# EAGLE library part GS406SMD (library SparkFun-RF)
50 Channel GS406 Helical GPS Receiver - SMD Connector. The Mating SMD SPECIAL is called SPECIAL for a reason. This package was only made in order to make a dummy gs407 PCB with mating connector (used for testing). sku: GPS-09079

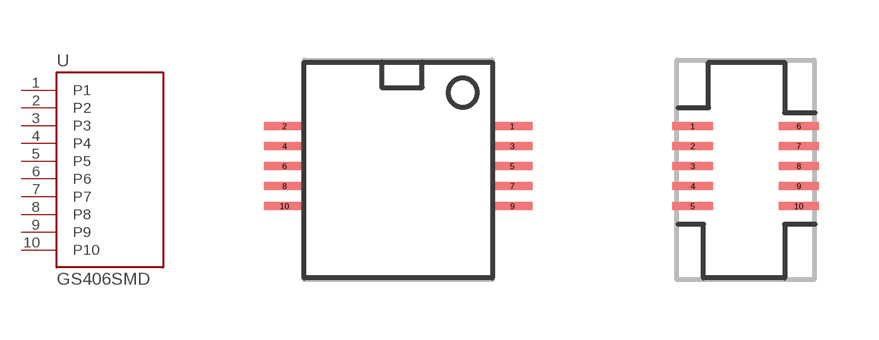
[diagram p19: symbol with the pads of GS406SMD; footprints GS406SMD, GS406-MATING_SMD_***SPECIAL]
Designator prefix U

## GS406SMDSOCKET  [GS406SMD]
1  P1
2  P2
3  P3
4  P4
5  P5
6  P6
7  P7
8  P8
9  P9
10  P10

## GS406SMDMATING_SMD_***SPECIAL  [GS406-MATING_SMD_***SPECIAL]
Pads as for GS406SMD

## Footprint GS406SMD (pad centres in mm)
50 Channel GS406 Helical GPS Receiver - SMD Connector sku: GPS-09079
smd 1 x 0.2: 1 2.76,1.06; 2 -2.94,1.06; 3 2.76,0.56; 4 -2.94,0.56; 5 2.76,0.06; 6 -2.94,0.06; 7 2.76,-0.44; 8 -2.94,-0.44; 9 2.76,-0.94; 10 -2.94,-0.94

## Footprint GS406-MATING_SMD_***SPECIAL (pad centres in mm)
smd 1 x 0.2: 1 -1.289,1.06; 2 -1.289,0.56; 3 -1.289,0.06; 4 -1.289,-0.44; 5 -1.289,-0.94; 6 1.363,1.06; 7 1.363,0.56; 8 1.363,0.06; 9 1.363,-0.44; 10 1.363,-0.94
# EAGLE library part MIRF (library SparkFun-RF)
nRF2401A 2.4GHz transceiver module, WRL-00153

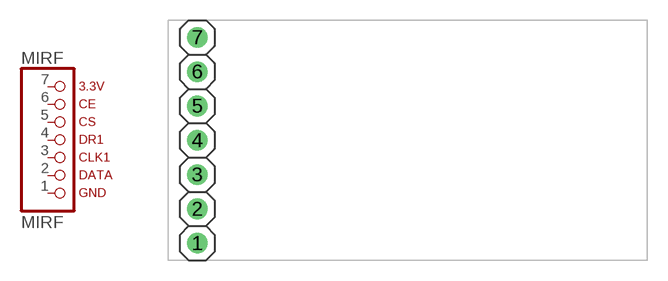
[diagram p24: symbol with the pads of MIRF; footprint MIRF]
Designator prefix MIRF

## MIRF  [MIRF]
1  7  pas
2  6  pas
3  5  pas
4  4  pas
5  3  pas
6  2  pas
7  1  pas

## Footprint MIRF (pad centres in mm)
PIN HEADER
drill 1.016: 1 0,-7.62; 2 0,-5.08; 3 0,-2.54; 4 0,0; 5 0,2.54; 6 0,5.08; 7 0,7.62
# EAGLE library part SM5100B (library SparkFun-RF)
Quad-band GSM modem

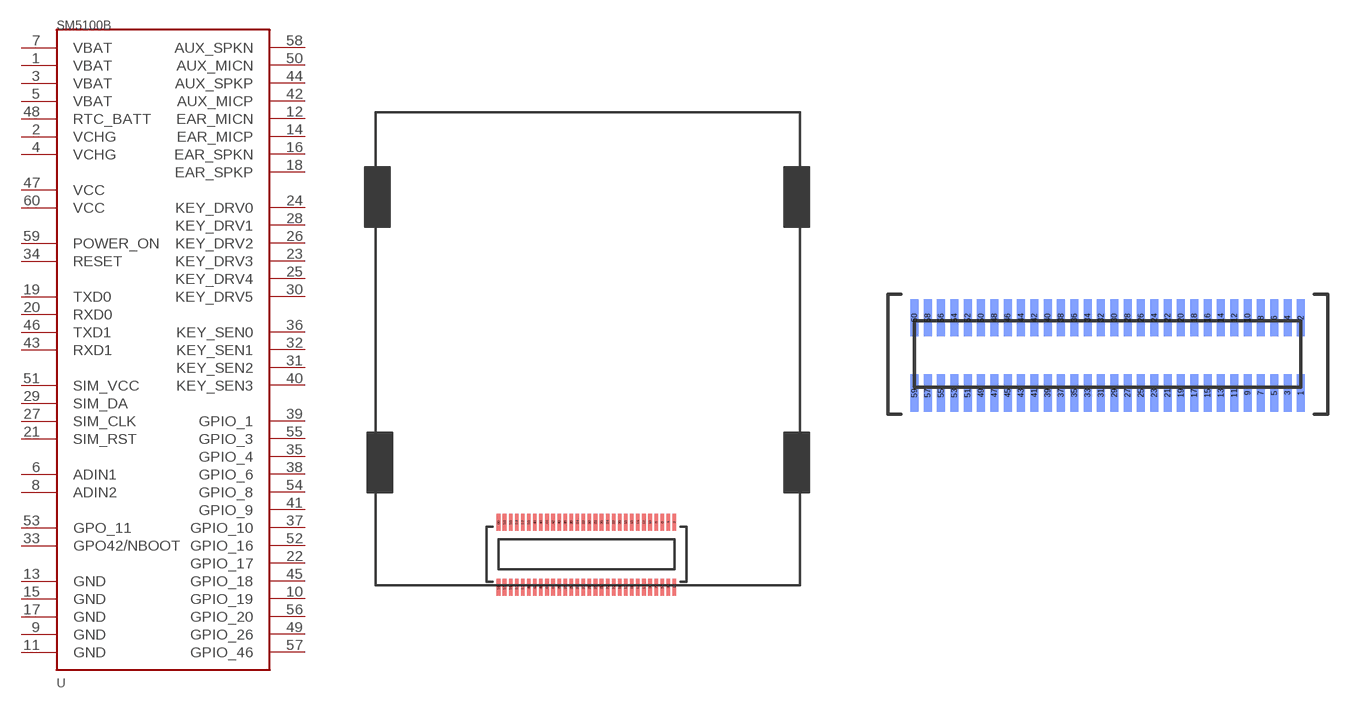
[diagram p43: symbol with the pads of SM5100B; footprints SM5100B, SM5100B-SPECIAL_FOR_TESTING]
Designator prefix -

## SM5100B (PROD_ID: CONN-09315)  [SM5100B]
1  VBAT
2  VCHG
3  VBAT
4  VCHG
5  VBAT
6  ADIN1
7  VBAT
8  ADIN2
9  GND
10  GPIO_19
11  GND
12  EAR_MICN
13  GND
14  EAR_MICP
15  GND
16  EAR_SPKN
17  GND
18  EAR_SPKP
19  TXD0
20  RXD0
21  SIM_RST
22  GPIO_17
23  KEY_DRV3
24  KEY_DRV0
25  KEY_DRV4
26  KEY_DRV2
27  SIM_CLK
28  KEY_DRV1
29  SIM_DA
30  KEY_DRV5
31  KEY_SEN2
32  KEY_SEN1
33  GPO42/NBOOT
34  RESET
35  GPIO_4
36  KEY_SEN0
37  GPIO_10
38  GPIO_6
39  GPIO_1
40  KEY_SEN3
41  GPIO_9
42  AUX_MICP
43  RXD1
44  AUX_SPKP
45  GPIO_18
46  TXD1
47  VCC
48  RTC_BATT
49  GPIO_26
50  AUX_MICN
51  SIM_VCC
52  GPIO_16
53  GPO_11
54  GPIO_8
55  GPIO_3
56  GPIO_20
57  GPIO_46
58  AUX_SPKN
59  POWER_ON
60  VCC

## SM5100BSPECIAL_FOR_TESTING!!  [SM5100B-SPECIAL_FOR_TESTING]
Pads as for SM5100B

## Footprint SM5100B (pad centres in mm)
smd 0.3 x 1.4: 1 7.25,-2.68; 2 7.25,2.68; 3 6.75,-2.68; 4 6.75,2.68; 5 6.25,-2.68; 6 6.25,2.68; 7 5.75,-2.68; 8 5.75,2.68; 9 5.25,-2.68; 10 5.25,2.68; 11 4.75,-2.68; 12 4.75,2.68; 13 4.25,-2.68; 14 4.25,2.68; 15 3.75,-2.68; 16 3.75,2.68; 17 3.25,-2.68; 18 3.25,2.68; 19 2.75,-2.68; 20 2.75,2.68; 21 2.25,-2.68; 22 2.25,2.68; 23 1.75,-2.68; 24 1.75,2.68; 25 1.25,-2.68; 26 1.25,2.68; 27 0.75,-2.68; 28 0.75,2.68; 29 0.25,-2.68; 30 0.25,2.68; 31 -0.25,-2.68; 32 -0.25,2.68; 33 -0.75,-2.68; 34 -0.75,2.68; 35 -1.25,-2.68; 36 -1.25,2.68; 37 -1.75,-2.68; 38 -1.75,2.68; 39 -2.25,-2.68; 40 -2.25,2.68; 41 -2.75,-2.68; 42 -2.75,2.68; 43 -3.25,-2.68; 44 -3.25,2.68; 45 -3.75,-2.68; 46 -3.75,2.68; 47 -4.25,-2.68; 48 -4.25,2.68; 49 -4.75,-2.68; 50 -4.75,2.68; 51 -5.25,-2.68; 52 -5.25,2.68; 53 -5.75,-2.68; 54 -5.75,2.68; 55 -6.25,-2.68; 56 -6.25,2.68; 57 -6.75,-2.68; 58 -6.75,2.68; 59 -7.25,-2.68; 60 -7.25,2.68

## Footprint SM5100B-SPECIAL_FOR_TESTING (pad centres in mm)
smd 0.3 x 1.4 bottom: 1 7.25,-1.41; 2 7.25,1.41; 3 6.75,-1.41; 4 6.75,1.41; 5 6.25,-1.41; 6 6.25,1.41; 7 5.75,-1.41; 8 5.75,1.41; 9 5.25,-1.41; 10 5.25,1.41; 11 4.75,-1.41; 12 4.75,1.41; 13 4.25,-1.41; 14 4.25,1.41; 15 3.75,-1.41; 16 3.75,1.41; 17 3.25,-1.41; 18 3.25,1.41; 19 2.75,-1.41; 20 2.75,1.41; 21 2.25,-1.41; 22 2.25,1.41; 23 1.75,-1.41; 24 1.75,1.41; 25 1.25,-1.41; 26 1.25,1.41; 27 0.75,-1.41; 28 0.75,1.41; 29 0.25,-1.41; 30 0.25,1.41; 31 -0.25,-1.41; 32 -0.25,1.41; 33 -0.75,-1.41; 34 -0.75,1.41; 35 -1.25,-1.41; 36 -1.25,1.41; 37 -1.75,-1.41; 38 -1.75,1.41; 39 -2.25,-1.41; 40 -2.25,1.41; 41 -2.75,-1.41; 42 -2.75,1.41; 43 -3.25,-1.41; 44 -3.25,1.41; 45 -3.75,-1.41; 46 -3.75,1.41; 47 -4.25,-1.41; 48 -4.25,1.41; 49 -4.75,-1.41; 50 -4.75,1.41; 51 -5.25,-1.41; 52 -5.25,1.41; 53 -5.75,-1.41; 54 -5.75,1.41; 55 -6.25,-1.41; 56 -6.25,1.41; 57 -6.75,-1.41; 58 -6.75,1.41; 59 -7.25,-1.41; 60 -7.25,1.41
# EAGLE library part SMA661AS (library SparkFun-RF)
GPS low noise amplifier, 18dB gain, low external parts count

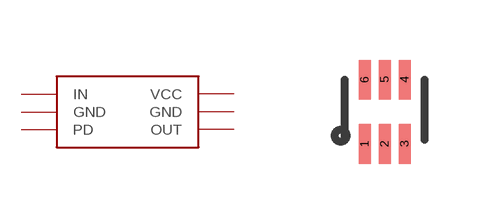
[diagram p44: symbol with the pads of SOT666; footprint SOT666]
Designator prefix -

## SMA661AS  [SOT666]
1  IN
2  GND
3  PD
4  OUT
5  GND
6  VCC

## Footprint SOT666 (pad centres in mm)
smd 0.3 x 0.99: 1 0,0; 2 0.5,0; 3 1,0; 4 1,1.61; 5 0.5,1.61; 6 0,1.61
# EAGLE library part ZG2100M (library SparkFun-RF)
WiFi transceiver module

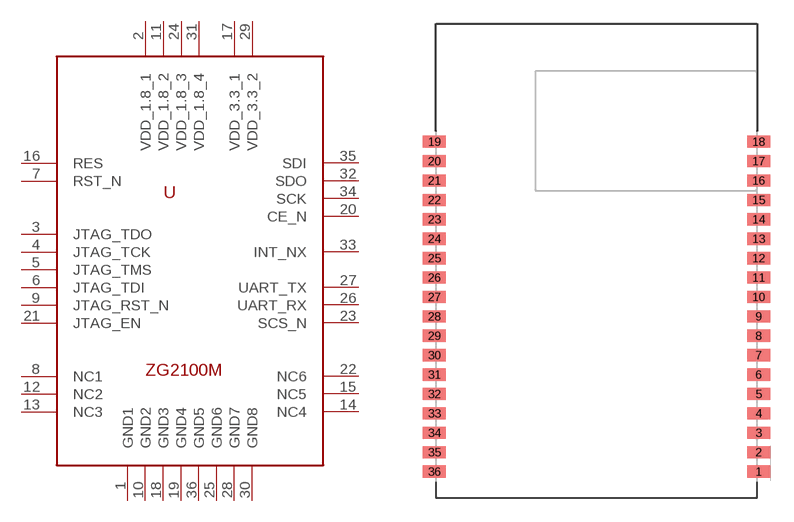
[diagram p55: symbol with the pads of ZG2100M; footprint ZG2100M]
Designator prefix -

## ZG2100M  [ZG2100M]
1  GND1
2  VDD_1.8_1
3  JTAG_TDO
4  JTAG_TCK
5  JTAG_TMS
6  JTAG_TDI
7  RST_N
8  NC1
9  JTAG_RST_N
10  GND2
11  VDD_1.8_2
12  NC2
13  NC3
14  NC4
15  NC5
16  RES
17  VDD_3.3_1
18  GND3
19  GND4
20  CE_N
21  JTAG_EN
22  NC6
23  SCS_N
24  VDD_1.8_3
25  GND6
26  UART_RX
27  UART_TX
28  GND7
29  VDD_3.3_2
30  GND8
31  VDD_1.8_4
32  SDO
33  INT_NX
34  SCK
35  SDI
36  GND5

## Footprint ZG2100M (pad centres in mm)
smd 1.5 x 0.8: 1 21.1,1.7; 2 21.1,2.97; 3 21.1,4.24; 4 21.1,5.51; 5 21.1,6.78; 6 21.1,8.05; 7 21.1,9.32; 8 21.1,10.59; 9 21.1,11.86; 10 21.1,13.13; 11 21.1,14.4; 12 21.1,15.67; 13 21.1,16.94; 14 21.1,18.21; 15 21.1,19.48; 16 21.1,20.75; 17 21.1,22.02; 18 21.1,23.29; 19 -0.1,23.29; 20 -0.1,22.02; 21 -0.1,20.75; 22 -0.1,19.48; 23 -0.1,18.21; 24 -0.1,16.94; 25 -0.1,15.67; 26 -0.1,14.4; 27 -0.1,13.13; 28 -0.1,11.86; 29 -0.1,10.59; 30 -0.1,9.32; 31 -0.1,8.05; 32 -0.1,6.78; 33 -0.1,5.51; 34 -0.1,4.24; 35 -0.1,2.97; 36 -0.1,1.7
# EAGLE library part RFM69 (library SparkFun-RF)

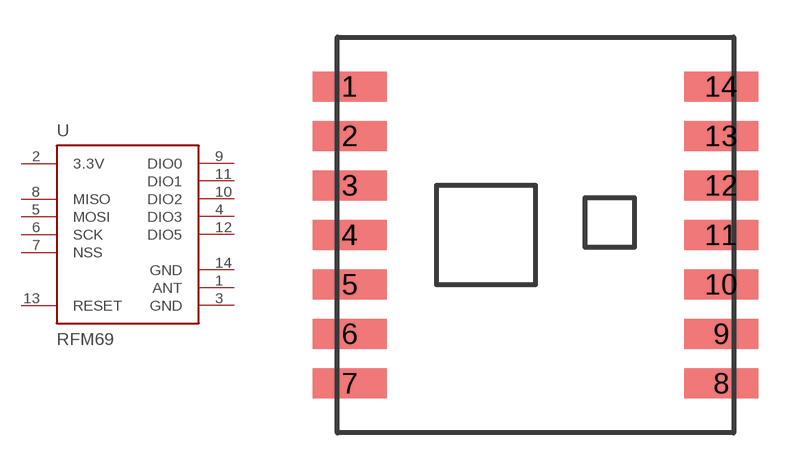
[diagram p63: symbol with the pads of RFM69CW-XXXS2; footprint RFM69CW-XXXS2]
Designator prefix U

## RFM69CW  [RFM69CW-XXXS2]
1  ANT  pas
2  3.3V  pwr
3  GND  pwr
4  DIO3
5  MOSI  in
6  SCK  in
7  NSS  in
8  MISO
9  DIO0
10  DIO2
11  DIO1
12  DIO5
13  RESET  in
14  GND  pwr

## Footprint RFM69CW-XXXS2 (pad centres in mm)
smd 3 x 1.2: 1 -7.5,6; 2 -7.5,4; 3 -7.5,2; 4 -7.5,0; 5 -7.5,-2; 6 -7.5,-4; 7 -7.5,-6; 8 7.5,-6; 9 7.5,-4; 10 7.5,-2; 11 7.5,0; 12 7.5,2; 13 7.5,4; 14 7.5,6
